VERSION 5.8 ;
BUSBITCHARS "[]" ;
DIVIDERCHAR "/" ;
UNITS
    DATABASE MICRONS 1000 ;
END UNITS

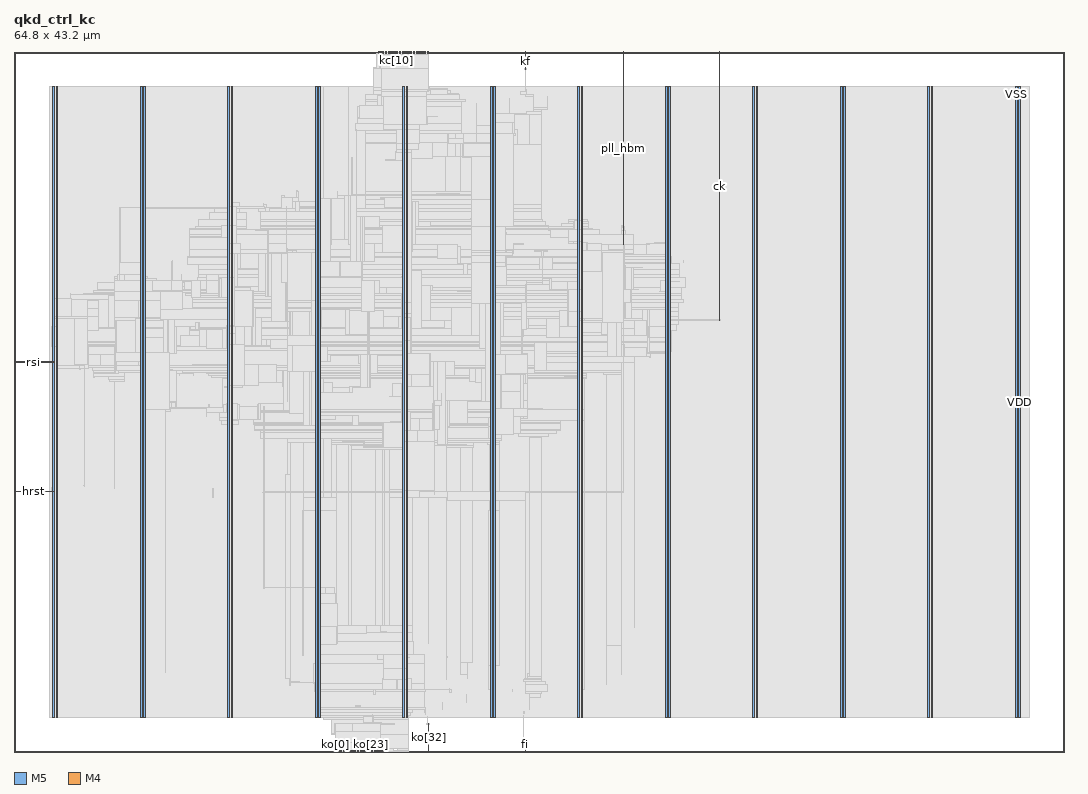
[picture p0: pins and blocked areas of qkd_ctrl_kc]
MACRO qkd_ctrl_kc
  FOREIGN qkd_ctrl_kc 0 0 ;
  CLASS BLOCK ;
  SIZE 64.8 BY 43.2 ;
  PIN ck
    DIRECTION INPUT ;
    USE SIGNAL ;
    PORT
      LAYER M5 ;
        RECT  43.536 43.116 43.56 43.2 ;
    END
    PORT
      LAYER M5 ;
        RECT  43.536 26.629 43.56 43.152 ;
    END
  END ck
  PIN fi
    DIRECTION INPUT ;
    USE SIGNAL ;
    PORT
      LAYER M5 ;
        RECT  31.536 0 31.56 0.084 ;
    END
    PORT
      LAYER M5 ;
        RECT  31.536 0.016 31.56 0.611 ;
    END
  END fi
  PIN hrst
    DIRECTION INPUT ;
    USE SIGNAL ;
    PORT
      LAYER M4 ;
        RECT  0 16.08 0.084 16.104 ;
    END
    PORT
      LAYER M4 ;
        RECT  0.06 16.08 2.408 16.104 ;
    END
  END hrst
  PIN kc[0]
    DIRECTION INPUT ;
    USE SIGNAL ;
    PORT
      LAYER M5 ;
        RECT  22.608 43.116 22.632 43.2 ;
    END
  END kc[0]
  PIN kc[10]
    DIRECTION INPUT ;
    USE SIGNAL ;
    PORT
      LAYER M5 ;
        RECT  23.568 43.116 23.592 43.2 ;
    END
  END kc[10]
  PIN kc[11]
    DIRECTION INPUT ;
    USE SIGNAL ;
    PORT
      LAYER M5 ;
        RECT  23.664 43.116 23.688 43.2 ;
    END
  END kc[11]
  PIN kc[12]
    DIRECTION INPUT ;
    USE SIGNAL ;
    PORT
      LAYER M5 ;
        RECT  23.76 43.116 23.784 43.2 ;
    END
  END kc[12]
  PIN kc[13]
    DIRECTION INPUT ;
    USE SIGNAL ;
    PORT
      LAYER M5 ;
        RECT  23.856 43.116 23.88 43.2 ;
    END
  END kc[13]
  PIN kc[14]
    DIRECTION INPUT ;
    USE SIGNAL ;
    PORT
      LAYER M5 ;
        RECT  23.952 43.116 23.976 43.2 ;
    END
  END kc[14]
  PIN kc[15]
    DIRECTION INPUT ;
    USE SIGNAL ;
    PORT
      LAYER M5 ;
        RECT  24.048 43.116 24.072 43.2 ;
    END
  END kc[15]
  PIN kc[16]
    DIRECTION INPUT ;
    USE SIGNAL ;
    PORT
      LAYER M5 ;
        RECT  24.144 43.116 24.168 43.2 ;
    END
  END kc[16]
  PIN kc[17]
    DIRECTION INPUT ;
    USE SIGNAL ;
    PORT
      LAYER M5 ;
        RECT  24.24 43.116 24.264 43.2 ;
    END
  END kc[17]
  PIN kc[18]
    DIRECTION INPUT ;
    USE SIGNAL ;
    PORT
      LAYER M5 ;
        RECT  24.336 43.116 24.36 43.2 ;
    END
  END kc[18]
  PIN kc[19]
    DIRECTION INPUT ;
    USE SIGNAL ;
    PORT
      LAYER M5 ;
        RECT  24.432 43.116 24.456 43.2 ;
    END
  END kc[19]
  PIN kc[1]
    DIRECTION INPUT ;
    USE SIGNAL ;
    PORT
      LAYER M5 ;
        RECT  22.704 43.116 22.728 43.2 ;
    END
  END kc[1]
  PIN kc[20]
    DIRECTION INPUT ;
    USE SIGNAL ;
    PORT
      LAYER M5 ;
        RECT  24.528 43.116 24.552 43.2 ;
    END
  END kc[20]
  PIN kc[21]
    DIRECTION INPUT ;
    USE SIGNAL ;
    PORT
      LAYER M5 ;
        RECT  24.624 43.116 24.648 43.2 ;
    END
  END kc[21]
  PIN kc[22]
    DIRECTION INPUT ;
    USE SIGNAL ;
    PORT
      LAYER M5 ;
        RECT  24.72 43.116 24.744 43.2 ;
    END
  END kc[22]
  PIN kc[23]
    DIRECTION INPUT ;
    USE SIGNAL ;
    PORT
      LAYER M5 ;
        RECT  24.816 43.116 24.84 43.2 ;
    END
  END kc[23]
  PIN kc[24]
    DIRECTION INPUT ;
    USE SIGNAL ;
    PORT
      LAYER M5 ;
        RECT  24.912 43.116 24.936 43.2 ;
    END
  END kc[24]
  PIN kc[25]
    DIRECTION INPUT ;
    USE SIGNAL ;
    PORT
      LAYER M5 ;
        RECT  25.008 43.116 25.032 43.2 ;
    END
  END kc[25]
  PIN kc[26]
    DIRECTION INPUT ;
    USE SIGNAL ;
    PORT
      LAYER M5 ;
        RECT  25.104 43.116 25.128 43.2 ;
    END
  END kc[26]
  PIN kc[27]
    DIRECTION INPUT ;
    USE SIGNAL ;
    PORT
      LAYER M5 ;
        RECT  25.2 43.116 25.224 43.2 ;
    END
  END kc[27]
  PIN kc[28]
    DIRECTION INPUT ;
    USE SIGNAL ;
    PORT
      LAYER M5 ;
        RECT  25.296 43.116 25.32 43.2 ;
    END
  END kc[28]
  PIN kc[29]
    DIRECTION INPUT ;
    USE SIGNAL ;
    PORT
      LAYER M5 ;
        RECT  25.392 43.116 25.416 43.2 ;
    END
  END kc[29]
  PIN kc[2]
    DIRECTION INPUT ;
    USE SIGNAL ;
    PORT
      LAYER M5 ;
        RECT  22.8 43.116 22.824 43.2 ;
    END
  END kc[2]
  PIN kc[30]
    DIRECTION INPUT ;
    USE SIGNAL ;
    PORT
      LAYER M5 ;
        RECT  25.488 43.116 25.512 43.2 ;
    END
  END kc[30]
  PIN kc[31]
    DIRECTION INPUT ;
    USE SIGNAL ;
    PORT
      LAYER M5 ;
        RECT  25.584 43.116 25.608 43.2 ;
    END
  END kc[31]
  PIN kc[32]
    DIRECTION INPUT ;
    USE SIGNAL ;
    PORT
      LAYER M5 ;
        RECT  22.512 43.116 22.536 43.2 ;
    END
  END kc[32]
  PIN kc[3]
    DIRECTION INPUT ;
    USE SIGNAL ;
    PORT
      LAYER M5 ;
        RECT  22.896 43.116 22.92 43.2 ;
    END
  END kc[3]
  PIN kc[4]
    DIRECTION INPUT ;
    USE SIGNAL ;
    PORT
      LAYER M5 ;
        RECT  22.992 43.116 23.016 43.2 ;
    END
  END kc[4]
  PIN kc[5]
    DIRECTION INPUT ;
    USE SIGNAL ;
    PORT
      LAYER M5 ;
        RECT  23.088 43.116 23.112 43.2 ;
    END
  END kc[5]
  PIN kc[6]
    DIRECTION INPUT ;
    USE SIGNAL ;
    PORT
      LAYER M5 ;
        RECT  23.184 43.116 23.208 43.2 ;
    END
  END kc[6]
  PIN kc[7]
    DIRECTION INPUT ;
    USE SIGNAL ;
    PORT
      LAYER M5 ;
        RECT  23.28 43.116 23.304 43.2 ;
    END
  END kc[7]
  PIN kc[8]
    DIRECTION INPUT ;
    USE SIGNAL ;
    PORT
      LAYER M5 ;
        RECT  23.376 43.116 23.4 43.2 ;
    END
  END kc[8]
  PIN kc[9]
    DIRECTION INPUT ;
    USE SIGNAL ;
    PORT
      LAYER M5 ;
        RECT  23.472 43.116 23.496 43.2 ;
    END
  END kc[9]
  PIN kf
    DIRECTION OUTPUT ;
    USE SIGNAL ;
    PORT
      LAYER M5 ;
        RECT  31.536 43.116 31.56 43.2 ;
    END
    PORT
      LAYER M5 ;
        RECT  31.536 42.133 31.56 43.152 ;
    END
  END kf
  PIN ko[0]
    DIRECTION OUTPUT ;
    USE SIGNAL ;
    PORT
      LAYER M5 ;
        RECT  19.824 0 19.848 0.084 ;
    END
  END ko[0]
  PIN ko[10]
    DIRECTION OUTPUT ;
    USE SIGNAL ;
    PORT
      LAYER M5 ;
        RECT  20.784 0 20.808 0.084 ;
    END
  END ko[10]
  PIN ko[11]
    DIRECTION OUTPUT ;
    USE SIGNAL ;
    PORT
      LAYER M5 ;
        RECT  20.88 0 20.904 0.084 ;
    END
  END ko[11]
  PIN ko[12]
    DIRECTION OUTPUT ;
    USE SIGNAL ;
    PORT
      LAYER M5 ;
        RECT  20.976 0 21 0.084 ;
    END
  END ko[12]
  PIN ko[13]
    DIRECTION OUTPUT ;
    USE SIGNAL ;
    PORT
      LAYER M5 ;
        RECT  21.072 0 21.096 0.084 ;
    END
  END ko[13]
  PIN ko[14]
    DIRECTION OUTPUT ;
    USE SIGNAL ;
    PORT
      LAYER M5 ;
        RECT  21.168 0 21.192 0.084 ;
    END
  END ko[14]
  PIN ko[15]
    DIRECTION OUTPUT ;
    USE SIGNAL ;
    PORT
      LAYER M5 ;
        RECT  21.264 0 21.288 0.084 ;
    END
  END ko[15]
  PIN ko[16]
    DIRECTION OUTPUT ;
    USE SIGNAL ;
    PORT
      LAYER M5 ;
        RECT  21.36 0 21.384 0.084 ;
    END
  END ko[16]
  PIN ko[17]
    DIRECTION OUTPUT ;
    USE SIGNAL ;
    PORT
      LAYER M5 ;
        RECT  21.456 0 21.48 0.084 ;
    END
  END ko[17]
  PIN ko[18]
    DIRECTION OUTPUT ;
    USE SIGNAL ;
    PORT
      LAYER M5 ;
        RECT  21.552 0 21.576 0.084 ;
    END
  END ko[18]
  PIN ko[19]
    DIRECTION OUTPUT ;
    USE SIGNAL ;
    PORT
      LAYER M5 ;
        RECT  21.648 0 21.672 0.084 ;
    END
  END ko[19]
  PIN ko[1]
    DIRECTION OUTPUT ;
    USE SIGNAL ;
    PORT
      LAYER M5 ;
        RECT  19.92 0 19.944 0.084 ;
    END
  END ko[1]
  PIN ko[20]
    DIRECTION OUTPUT ;
    USE SIGNAL ;
    PORT
      LAYER M5 ;
        RECT  21.744 0 21.768 0.084 ;
    END
  END ko[20]
  PIN ko[21]
    DIRECTION OUTPUT ;
    USE SIGNAL ;
    PORT
      LAYER M5 ;
        RECT  21.84 0 21.864 0.084 ;
    END
  END ko[21]
  PIN ko[22]
    DIRECTION OUTPUT ;
    USE SIGNAL ;
    PORT
      LAYER M5 ;
        RECT  21.936 0 21.96 0.084 ;
    END
  END ko[22]
  PIN ko[23]
    DIRECTION OUTPUT ;
    USE SIGNAL ;
    PORT
      LAYER M5 ;
        RECT  22.032 0 22.056 0.084 ;
    END
  END ko[23]
  PIN ko[24]
    DIRECTION OUTPUT ;
    USE SIGNAL ;
    PORT
      LAYER M5 ;
        RECT  22.128 0 22.152 0.084 ;
    END
  END ko[24]
  PIN ko[25]
    DIRECTION OUTPUT ;
    USE SIGNAL ;
    PORT
      LAYER M5 ;
        RECT  22.224 0 22.248 0.084 ;
    END
  END ko[25]
  PIN ko[26]
    DIRECTION OUTPUT ;
    USE SIGNAL ;
    PORT
      LAYER M5 ;
        RECT  22.32 0 22.344 0.084 ;
    END
  END ko[26]
  PIN ko[27]
    DIRECTION OUTPUT ;
    USE SIGNAL ;
    PORT
      LAYER M5 ;
        RECT  22.416 0 22.44 0.084 ;
    END
  END ko[27]
  PIN ko[28]
    DIRECTION OUTPUT ;
    USE SIGNAL ;
    PORT
      LAYER M5 ;
        RECT  22.512 0 22.536 0.084 ;
    END
  END ko[28]
  PIN ko[29]
    DIRECTION OUTPUT ;
    USE SIGNAL ;
    PORT
      LAYER M5 ;
        RECT  22.608 0 22.632 0.084 ;
    END
  END ko[29]
  PIN ko[2]
    DIRECTION OUTPUT ;
    USE SIGNAL ;
    PORT
      LAYER M5 ;
        RECT  20.016 0 20.04 0.084 ;
    END
  END ko[2]
  PIN ko[30]
    DIRECTION OUTPUT ;
    USE SIGNAL ;
    PORT
      LAYER M5 ;
        RECT  22.704 0 22.728 0.084 ;
    END
  END ko[30]
  PIN ko[31]
    DIRECTION OUTPUT ;
    USE SIGNAL ;
    PORT
      LAYER M5 ;
        RECT  22.8 0 22.824 0.084 ;
    END
  END ko[31]
  PIN ko[32]
    DIRECTION OUTPUT ;
    USE SIGNAL ;
    PORT
      LAYER M5 ;
        RECT  25.584 0 25.608 0.084 ;
    END
    PORT
      LAYER M5 ;
        RECT  25.584 0.016 25.608 1.763 ;
    END
  END ko[32]
  PIN ko[3]
    DIRECTION OUTPUT ;
    USE SIGNAL ;
    PORT
      LAYER M5 ;
        RECT  20.112 0 20.136 0.084 ;
    END
  END ko[3]
  PIN ko[4]
    DIRECTION OUTPUT ;
    USE SIGNAL ;
    PORT
      LAYER M5 ;
        RECT  20.208 0 20.232 0.084 ;
    END
  END ko[4]
  PIN ko[5]
    DIRECTION OUTPUT ;
    USE SIGNAL ;
    PORT
      LAYER M5 ;
        RECT  20.304 0 20.328 0.084 ;
    END
  END ko[5]
  PIN ko[6]
    DIRECTION OUTPUT ;
    USE SIGNAL ;
    PORT
      LAYER M5 ;
        RECT  20.4 0 20.424 0.084 ;
    END
  END ko[6]
  PIN ko[7]
    DIRECTION OUTPUT ;
    USE SIGNAL ;
    PORT
      LAYER M5 ;
        RECT  20.496 0 20.52 0.084 ;
    END
  END ko[7]
  PIN ko[8]
    DIRECTION OUTPUT ;
    USE SIGNAL ;
    PORT
      LAYER M5 ;
        RECT  20.592 0 20.616 0.084 ;
    END
  END ko[8]
  PIN ko[9]
    DIRECTION OUTPUT ;
    USE SIGNAL ;
    PORT
      LAYER M5 ;
        RECT  20.688 0 20.712 0.084 ;
    END
  END ko[9]
  PIN pll_hbm
    DIRECTION INPUT ;
    USE SIGNAL ;
    PORT
      LAYER M5 ;
        RECT  37.584 43.116 37.608 43.2 ;
    END
    PORT
      LAYER M5 ;
        RECT  37.584 31.331 37.608 43.152 ;
    END
  END pll_hbm
  PIN rsi
    DIRECTION INPUT ;
    USE SIGNAL ;
    PORT
      LAYER M4 ;
        RECT  0 24.048 0.084 24.072 ;
    END
    PORT
      LAYER M4 ;
        RECT  0.06 24.048 2.408 24.072 ;
    END
  END rsi
  PIN VDD
    DIRECTION INOUT ;
    USE POWER ;
    PORT
      LAYER M5 ;
        RECT  61.992 2.151 62.112 41.049 ;
        RECT  56.592 2.151 56.712 41.049 ;
        RECT  51.192 2.151 51.312 41.049 ;
        RECT  45.792 2.151 45.912 41.049 ;
        RECT  40.392 2.151 40.512 41.049 ;
        RECT  34.992 2.151 35.112 41.049 ;
        RECT  29.592 2.151 29.712 41.049 ;
        RECT  24.192 2.151 24.312 41.049 ;
        RECT  18.792 2.151 18.912 41.049 ;
        RECT  13.392 2.151 13.512 41.049 ;
        RECT  7.992 2.151 8.112 41.049 ;
        RECT  2.592 2.151 2.712 41.049 ;
    END
  END VDD
  PIN VSS
    DIRECTION INOUT ;
    USE GROUND ;
    PORT
      LAYER M5 ;
        RECT  61.8 2.137 61.92 41.063 ;
        RECT  56.4 2.137 56.52 41.063 ;
        RECT  51 2.137 51.12 41.063 ;
        RECT  45.6 2.137 45.72 41.063 ;
        RECT  40.2 2.137 40.32 41.063 ;
        RECT  34.8 2.137 34.92 41.063 ;
        RECT  29.4 2.137 29.52 41.063 ;
        RECT  24 2.137 24.12 41.063 ;
        RECT  18.6 2.137 18.72 41.063 ;
        RECT  13.2 2.137 13.32 41.063 ;
        RECT  7.8 2.137 7.92 41.063 ;
        RECT  2.4 2.137 2.52 41.063 ;
    END
  END VSS
  # OT_OBS_CLOSED layer=M5 d_um=1.536 added=60
  OBS
    LAYER RVTN ;
     RECT  2.16 2.16 62.64 2.295 ;
     RECT  2.16 2.565 62.64 2.835 ;
     RECT  2.16 3.105 62.64 3.375 ;
     RECT  2.16 3.645 62.64 3.915 ;
     RECT  2.16 4.185 62.64 4.455 ;
     RECT  2.16 4.725 62.64 4.995 ;
     RECT  2.16 5.265 62.64 5.535 ;
     RECT  2.16 5.805 62.64 6.075 ;
     RECT  2.16 6.345 62.64 6.615 ;
     RECT  2.16 6.885 62.64 7.155 ;
     RECT  2.16 7.425 62.64 7.695 ;
     RECT  2.16 7.965 62.64 8.235 ;
     RECT  2.16 8.505 62.64 8.775 ;
     RECT  2.16 9.045 62.64 9.315 ;
     RECT  2.16 9.585 62.64 9.855 ;
     RECT  2.16 10.125 62.64 10.395 ;
     RECT  2.16 10.665 62.64 10.935 ;
     RECT  2.16 11.205 62.64 11.475 ;
     RECT  2.16 11.745 62.64 12.015 ;
     RECT  2.16 12.285 62.64 12.555 ;
     RECT  2.16 12.825 62.64 13.095 ;
     RECT  2.16 13.365 62.64 13.635 ;
     RECT  2.16 13.905 62.64 14.175 ;
     RECT  2.16 14.445 62.64 14.715 ;
     RECT  2.16 14.985 62.64 15.255 ;
     RECT  2.16 15.525 62.64 15.795 ;
     RECT  2.16 16.065 62.64 16.335 ;
     RECT  2.16 16.605 62.64 16.875 ;
     RECT  2.16 17.145 62.64 17.415 ;
     RECT  2.16 17.685 62.64 17.955 ;
     RECT  2.16 18.225 62.64 18.495 ;
     RECT  2.16 18.765 62.64 19.035 ;
     RECT  2.16 19.305 62.64 19.575 ;
     RECT  2.16 19.845 62.64 20.115 ;
     RECT  2.16 20.385 62.64 20.655 ;
     RECT  2.16 20.925 62.64 21.195 ;
     RECT  2.16 21.465 62.64 21.735 ;
     RECT  2.16 22.005 62.64 22.275 ;
     RECT  2.16 22.545 62.64 22.815 ;
     RECT  2.16 23.085 62.64 23.355 ;
     RECT  2.16 23.625 62.64 23.895 ;
     RECT  2.16 24.165 62.64 24.435 ;
     RECT  2.16 24.705 62.64 24.975 ;
     RECT  2.16 25.245 62.64 25.515 ;
     RECT  2.16 25.785 62.64 26.055 ;
     RECT  2.16 26.325 62.64 26.595 ;
     RECT  2.16 26.865 62.64 27.135 ;
     RECT  2.16 27.405 62.64 27.675 ;
     RECT  2.16 27.945 62.64 28.215 ;
     RECT  2.16 28.485 62.64 28.755 ;
     RECT  2.16 29.025 62.64 29.295 ;
     RECT  2.16 29.565 62.64 29.835 ;
     RECT  2.16 30.105 62.64 30.375 ;
     RECT  2.16 30.645 62.64 30.915 ;
     RECT  2.16 31.185 62.64 31.455 ;
     RECT  2.16 31.725 62.64 31.995 ;
     RECT  2.16 32.265 62.64 32.535 ;
     RECT  2.16 32.805 62.64 33.075 ;
     RECT  2.16 33.345 62.64 33.615 ;
     RECT  2.16 33.885 62.64 34.155 ;
     RECT  2.16 34.425 62.64 34.695 ;
     RECT  2.16 34.965 62.64 35.235 ;
     RECT  2.16 35.505 62.64 35.775 ;
     RECT  2.16 36.045 62.64 36.315 ;
     RECT  2.16 36.585 62.64 36.855 ;
     RECT  2.16 37.125 62.64 37.395 ;
     RECT  2.16 37.665 62.64 37.935 ;
     RECT  2.16 38.205 62.64 38.475 ;
     RECT  2.16 38.745 62.64 39.015 ;
     RECT  2.16 39.285 62.64 39.555 ;
     RECT  2.16 39.825 62.64 40.095 ;
     RECT  2.16 40.365 62.64 40.635 ;
     RECT  2.16 40.905 62.64 41.04 ;
    LAYER RVTP ;
     RECT  2.16 2.295 62.64 2.565 ;
     RECT  2.16 2.835 62.64 3.105 ;
     RECT  2.16 3.375 62.64 3.645 ;
     RECT  2.16 3.915 62.64 4.185 ;
     RECT  2.16 4.455 62.64 4.725 ;
     RECT  2.16 4.995 62.64 5.265 ;
     RECT  2.16 5.535 62.64 5.805 ;
     RECT  2.16 6.075 62.64 6.345 ;
     RECT  2.16 6.615 62.64 6.885 ;
     RECT  2.16 7.155 62.64 7.425 ;
     RECT  2.16 7.695 62.64 7.965 ;
     RECT  2.16 8.235 62.64 8.505 ;
     RECT  2.16 8.775 62.64 9.045 ;
     RECT  2.16 9.315 62.64 9.585 ;
     RECT  2.16 9.855 62.64 10.125 ;
     RECT  2.16 10.395 62.64 10.665 ;
     RECT  2.16 10.935 62.64 11.205 ;
     RECT  2.16 11.475 62.64 11.745 ;
     RECT  2.16 12.015 62.64 12.285 ;
     RECT  2.16 12.555 62.64 12.825 ;
     RECT  2.16 13.095 62.64 13.365 ;
     RECT  2.16 13.635 62.64 13.905 ;
     RECT  2.16 14.175 62.64 14.445 ;
     RECT  2.16 14.715 62.64 14.985 ;
     RECT  2.16 15.255 62.64 15.525 ;
     RECT  2.16 15.795 62.64 16.065 ;
     RECT  2.16 16.335 62.64 16.605 ;
     RECT  2.16 16.875 62.64 17.145 ;
     RECT  2.16 17.415 62.64 17.685 ;
     RECT  2.16 17.955 62.64 18.225 ;
     RECT  2.16 18.495 62.64 18.765 ;
     RECT  2.16 19.035 62.64 19.305 ;
     RECT  2.16 19.575 62.64 19.845 ;
     RECT  2.16 20.115 62.64 20.385 ;
     RECT  2.16 20.655 62.64 20.925 ;
     RECT  2.16 21.195 62.64 21.465 ;
     RECT  2.16 21.735 62.64 22.005 ;
     RECT  2.16 22.275 62.64 22.545 ;
     RECT  2.16 22.815 62.64 23.085 ;
     RECT  2.16 23.355 62.64 23.625 ;
     RECT  2.16 23.895 62.64 24.165 ;
     RECT  2.16 24.435 62.64 24.705 ;
     RECT  2.16 24.975 62.64 25.245 ;
     RECT  2.16 25.515 62.64 25.785 ;
     RECT  2.16 26.055 62.64 26.325 ;
     RECT  2.16 26.595 62.64 26.865 ;
     RECT  2.16 27.135 62.64 27.405 ;
     RECT  2.16 27.675 62.64 27.945 ;
     RECT  2.16 28.215 62.64 28.485 ;
     RECT  2.16 28.755 62.64 29.025 ;
     RECT  2.16 29.295 62.64 29.565 ;
     RECT  2.16 29.835 62.64 30.105 ;
     RECT  2.16 30.375 62.64 30.645 ;
     RECT  2.16 30.915 62.64 31.185 ;
     RECT  2.16 31.455 62.64 31.725 ;
     RECT  2.16 31.995 62.64 32.265 ;
     RECT  2.16 32.535 62.64 32.805 ;
     RECT  2.16 33.075 62.64 33.345 ;
     RECT  2.16 33.615 62.64 33.885 ;
     RECT  2.16 34.155 62.64 34.425 ;
     RECT  2.16 34.695 62.64 34.965 ;
     RECT  2.16 35.235 62.64 35.505 ;
     RECT  2.16 35.775 62.64 36.045 ;
     RECT  2.16 36.315 62.64 36.585 ;
     RECT  2.16 36.855 62.64 37.125 ;
     RECT  2.16 37.395 62.64 37.665 ;
     RECT  2.16 37.935 62.64 38.205 ;
     RECT  2.16 38.475 62.64 38.745 ;
     RECT  2.16 39.015 62.64 39.285 ;
     RECT  2.16 39.555 62.64 39.825 ;
     RECT  2.16 40.095 62.64 40.365 ;
     RECT  2.16 40.635 62.64 40.905 ;
    LAYER M1 ;
     RECT  2.16 2.151 62.64 41.049 ;
    LAYER M2 ;
     RECT  2.16 2.151 19.111 41.049 ;
     RECT  19.111 2.034 20.651 41.049 ;
     RECT  20.651 2.151 22.747 41.049 ;
     RECT  22.747 2.106 22.847 41.049 ;
     RECT  22.847 2.151 62.64 41.049 ;
    LAYER M3 ;
     RECT  22.536 0.043 22.554 0.091 ;
     RECT  24.336 0.043 24.354 0.091 ;
     RECT  19.944 0.091 20.754 0.139 ;
     RECT  21.888 0.091 22.554 0.139 ;
     RECT  19.836 0.139 22.698 0.187 ;
     RECT  23.688 0.091 24.354 0.187 ;
     RECT  19.836 0.187 24.354 1.099 ;
     RECT  19.62 1.099 24.354 2.029 ;
     RECT  19.116 2.029 24.354 2.143 ;
     RECT  25.488 1.723 25.506 2.219 ;
     RECT  31.428 0.571 31.446 2.255 ;
     RECT  18.615 2.143 24.354 2.263 ;
     RECT  2.415 2.143 2.505 2.413 ;
     RECT  7.815 2.143 7.905 2.413 ;
     RECT  13.215 2.143 13.305 2.413 ;
     RECT  29.415 2.143 29.505 2.413 ;
     RECT  34.815 2.143 34.905 2.413 ;
     RECT  40.215 2.143 40.305 2.413 ;
     RECT  45.615 2.143 45.705 2.413 ;
     RECT  51.015 2.143 51.105 2.413 ;
     RECT  56.415 2.143 56.505 2.413 ;
     RECT  61.815 2.143 61.905 2.413 ;
     RECT  18.615 2.263 24.498 2.461 ;
     RECT  25.38 2.335 25.398 2.461 ;
     RECT  31.464 2.371 31.482 2.489 ;
     RECT  18.615 2.461 24.57 2.641 ;
     RECT  25.344 2.461 25.398 2.641 ;
     RECT  18.615 2.641 25.398 2.759 ;
     RECT  26.424 2.641 26.442 3.029 ;
     RECT  31.788 2.641 31.806 3.379 ;
     RECT  27.936 3.073 27.954 3.569 ;
     RECT  31.788 3.379 32.49 3.604 ;
     RECT  31.788 3.604 32.526 3.613 ;
     RECT  18.615 2.759 25.362 3.721 ;
     RECT  31.536 3.613 32.526 3.721 ;
     RECT  18.54 3.721 25.398 3.839 ;
     RECT  30.744 3.721 30.762 3.839 ;
     RECT  29.415 2.413 29.697 3.847 ;
     RECT  26.856 3.685 26.982 3.869 ;
     RECT  34.815 2.413 35.097 3.883 ;
     RECT  26.856 3.869 26.874 3.911 ;
     RECT  31.536 3.721 32.922 4.181 ;
     RECT  18.54 3.839 25.362 4.225 ;
     RECT  17.028 4.081 17.046 4.267 ;
     RECT  31.536 4.181 32.814 4.351 ;
     RECT  17.028 4.267 17.622 4.379 ;
     RECT  31.464 4.351 32.814 4.379 ;
     RECT  31.464 4.379 32.562 4.487 ;
     RECT  17.028 4.379 17.046 4.531 ;
     RECT  31.536 4.487 32.562 4.559 ;
     RECT  31.68 4.559 32.562 4.649 ;
     RECT  31.68 4.649 31.806 4.685 ;
     RECT  27.972 4.531 27.99 4.801 ;
     RECT  31.716 4.685 31.806 4.829 ;
     RECT  29.268 3.847 29.697 5.341 ;
     RECT  18.504 4.225 25.362 5.459 ;
     RECT  27.54 4.801 27.99 5.503 ;
     RECT  26.676 4.459 26.694 5.809 ;
     RECT  26.676 5.809 26.766 5.909 ;
     RECT  18.615 5.459 25.362 5.999 ;
     RECT  36.54 4.189 36.558 6.547 ;
     RECT  37.476 4.765 37.494 6.547 ;
     RECT  18.615 5.999 24.642 6.809 ;
     RECT  18.615 6.809 24.57 7.385 ;
     RECT  20.664 7.385 24.57 7.805 ;
     RECT  18.615 7.385 19.89 9.115 ;
     RECT  17.82 5.971 17.838 14.881 ;
     RECT  18.615 9.115 19.926 14.881 ;
     RECT  17.82 14.881 19.926 14.909 ;
     RECT  29.268 5.341 29.97 14.909 ;
     RECT  26.676 5.909 26.694 15.547 ;
     RECT  23.148 7.805 24.57 15.691 ;
     RECT  25.56 6.691 25.578 15.691 ;
     RECT  17.892 14.909 19.926 15.719 ;
     RECT  26.676 15.547 26.802 15.725 ;
     RECT  15.408 15.961 15.426 16.013 ;
     RECT  15.516 16.024 15.534 16.061 ;
     RECT  2.415 2.413 2.697 16.075 ;
     RECT  23.148 15.691 25.578 16.205 ;
     RECT  12.276 15.691 12.294 16.259 ;
     RECT  2.304 16.075 2.697 16.295 ;
     RECT  4.32 16.405 4.338 16.445 ;
     RECT  16.776 4.531 17.046 17.141 ;
     RECT  20.808 7.805 22.302 18.697 ;
     RECT  23.148 16.205 24.57 18.697 ;
     RECT  26.676 15.725 26.694 18.805 ;
     RECT  27.54 5.503 28.314 18.805 ;
     RECT  20.808 18.697 24.57 18.931 ;
     RECT  25.56 16.205 25.578 18.931 ;
     RECT  26.676 18.805 28.386 18.931 ;
     RECT  29.34 14.909 29.97 18.967 ;
     RECT  19.62 15.719 19.926 19.003 ;
     RECT  20.772 18.931 24.57 19.003 ;
     RECT  19.62 19.003 24.57 19.075 ;
     RECT  25.56 18.931 28.386 19.075 ;
     RECT  16.848 17.141 17.046 19.111 ;
     RECT  17.892 15.719 18.897 19.111 ;
     RECT  19.62 19.075 28.386 19.111 ;
     RECT  29.196 18.967 29.97 19.111 ;
     RECT  19.62 19.111 29.97 19.201 ;
     RECT  15.228 19.339 15.822 19.345 ;
     RECT  16.848 19.111 18.897 19.345 ;
     RECT  19.62 19.201 30.078 19.345 ;
     RECT  15.228 19.345 30.078 19.373 ;
     RECT  31.788 4.829 31.806 19.381 ;
     RECT  32.544 4.649 32.562 19.381 ;
     RECT  31.788 19.381 32.562 19.471 ;
     RECT  31.104 19.471 32.958 19.651 ;
     RECT  15.228 19.373 24.678 19.741 ;
     RECT  15.192 19.741 24.678 19.849 ;
     RECT  31.104 19.651 33.462 19.849 ;
     RECT  31.104 19.849 33.75 19.885 ;
     RECT  14.868 19.849 24.678 19.921 ;
     RECT  25.524 19.373 30.078 20.011 ;
     RECT  14.832 19.921 24.678 20.155 ;
     RECT  25.524 20.011 30.15 20.155 ;
     RECT  13.215 2.413 13.497 20.191 ;
     RECT  14.832 20.155 30.15 20.191 ;
     RECT  14.76 20.191 30.15 20.281 ;
     RECT  31.068 19.885 33.75 20.281 ;
     RECT  14.76 20.281 33.75 20.345 ;
     RECT  12.78 20.191 13.842 20.461 ;
     RECT  30.78 20.345 33.75 20.461 ;
     RECT  34.815 3.883 35.19 20.461 ;
     RECT  12.708 20.461 13.842 20.659 ;
     RECT  11.88 20.731 11.898 20.923 ;
     RECT  12.708 20.659 13.878 20.923 ;
     RECT  11.88 20.923 13.878 20.929 ;
     RECT  14.76 20.345 30.006 20.929 ;
     RECT  11.88 20.929 30.006 20.957 ;
     RECT  9.36 4.891 9.378 21.001 ;
     RECT  12.024 20.957 30.006 21.029 ;
     RECT  12.852 21.029 30.006 21.127 ;
     RECT  30.78 20.461 35.19 21.127 ;
     RECT  9.36 21.001 9.63 21.211 ;
     RECT  12.024 21.029 12.042 21.425 ;
     RECT  9.36 21.211 9.702 21.541 ;
     RECT  9.36 21.541 9.99 21.677 ;
     RECT  6.192 16.267 6.21 22.891 ;
     RECT  5.904 22.891 6.822 23.017 ;
     RECT  12.852 21.127 35.19 23.053 ;
     RECT  12.852 23.053 35.334 23.125 ;
     RECT  4.932 23.089 4.95 23.161 ;
     RECT  5.832 23.017 6.822 23.161 ;
     RECT  12.168 23.125 35.334 23.251 ;
     RECT  36.54 6.547 37.494 23.287 ;
     RECT  9.36 21.677 9.378 23.359 ;
     RECT  10.224 23.251 10.242 23.359 ;
     RECT  11.988 23.251 35.334 23.359 ;
     RECT  9.36 23.359 10.242 23.371 ;
     RECT  11.088 23.251 11.106 23.371 ;
     RECT  9.36 23.371 11.106 23.395 ;
     RECT  11.88 23.359 35.334 23.395 ;
     RECT  4.932 23.161 6.822 23.431 ;
     RECT  7.815 2.413 8.097 23.431 ;
     RECT  8.892 23.395 35.442 23.431 ;
     RECT  36.36 23.287 37.494 23.431 ;
     RECT  8.892 23.431 37.494 23.549 ;
     RECT  4.932 23.431 8.097 23.557 ;
     RECT  8.892 23.549 32.094 23.557 ;
     RECT  4.068 23.629 4.086 23.701 ;
     RECT  4.824 23.557 32.094 23.701 ;
     RECT  4.068 23.701 32.094 23.851 ;
     RECT  3.744 23.851 32.094 23.855 ;
     RECT  2.415 16.295 2.697 23.899 ;
     RECT  3.744 23.855 4.554 23.935 ;
     RECT  2.415 23.899 2.79 23.971 ;
     RECT  3.636 23.935 4.554 23.971 ;
     RECT  2.415 23.971 4.554 24.043 ;
     RECT  32.868 23.549 37.494 24.061 ;
     RECT  38.304 7.663 38.322 24.061 ;
     RECT  2.304 24.043 4.554 24.125 ;
     RECT  32.868 24.061 38.322 24.379 ;
     RECT  39.24 24.331 39.258 24.379 ;
     RECT  32.868 24.379 39.258 24.601 ;
     RECT  40.215 2.413 40.497 24.601 ;
     RECT  32.868 24.601 40.497 24.709 ;
     RECT  2.415 24.125 4.554 24.781 ;
     RECT  5.364 23.855 32.094 24.781 ;
     RECT  2.415 24.781 32.094 25.015 ;
     RECT  2.34 25.015 32.094 25.085 ;
     RECT  2.415 25.085 32.094 25.169 ;
     RECT  3.492 25.169 32.094 25.285 ;
     RECT  32.868 24.709 40.59 25.285 ;
     RECT  3.492 25.285 40.59 25.313 ;
     RECT  15.084 25.313 40.59 25.709 ;
     RECT  39.06 25.709 40.59 25.987 ;
     RECT  15.084 25.709 38.322 26.123 ;
     RECT  2.415 25.169 2.697 26.131 ;
     RECT  3.492 25.313 14.346 26.131 ;
     RECT  15.084 26.123 26.586 26.131 ;
     RECT  2.415 26.131 26.586 26.203 ;
     RECT  39.06 25.987 40.878 26.401 ;
     RECT  27.36 26.123 38.322 26.635 ;
     RECT  39.06 26.401 40.986 26.635 ;
     RECT  2.376 26.203 26.586 26.699 ;
     RECT  27.36 26.635 40.986 26.905 ;
     RECT  27.324 26.905 40.986 27.211 ;
     RECT  2.415 26.699 26.586 27.341 ;
     RECT  10.836 27.341 26.586 27.401 ;
     RECT  11.016 27.401 26.586 27.445 ;
     RECT  27.324 27.211 41.022 27.445 ;
     RECT  11.016 27.445 41.022 27.751 ;
     RECT  2.415 27.341 9.702 27.941 ;
     RECT  11.016 27.751 41.346 27.941 ;
     RECT  11.016 27.941 41.202 28.147 ;
     RECT  10.98 28.147 41.202 28.183 ;
     RECT  3.492 27.941 9.702 28.247 ;
     RECT  3.492 28.247 3.51 28.283 ;
     RECT  4.284 28.247 9.702 28.283 ;
     RECT  10.584 28.183 41.202 28.319 ;
     RECT  4.896 28.283 9.702 28.363 ;
     RECT  10.584 28.319 11.862 28.363 ;
     RECT  4.896 28.363 11.862 28.481 ;
     RECT  10.08 28.481 11.862 28.517 ;
     RECT  5.148 28.481 9.342 28.541 ;
     RECT  12.6 28.319 41.202 28.687 ;
     RECT  10.08 28.517 10.53 28.715 ;
     RECT  5.148 28.541 8.802 28.949 ;
     RECT  10.332 28.715 10.53 28.949 ;
     RECT  5.148 28.949 5.166 28.985 ;
     RECT  6.192 28.949 8.802 29.219 ;
     RECT  11.304 28.517 11.862 29.255 ;
     RECT  12.6 28.687 41.454 29.255 ;
     RECT  6.192 29.219 8.262 29.363 ;
     RECT  11.412 29.255 11.862 29.461 ;
     RECT  12.6 29.255 41.058 29.461 ;
     RECT  6.372 29.363 8.097 29.489 ;
     RECT  10.332 28.949 10.35 29.489 ;
     RECT  6.516 29.489 8.097 29.759 ;
     RECT  11.412 29.461 41.058 29.795 ;
     RECT  11.412 29.795 32.454 30.109 ;
     RECT  33.228 29.795 41.058 30.173 ;
     RECT  33.228 30.173 40.59 30.209 ;
     RECT  6.516 29.759 6.534 30.221 ;
     RECT  9.756 30.235 9.774 30.335 ;
     RECT  41.328 30.181 41.346 30.335 ;
     RECT  37.62 30.209 40.59 30.407 ;
     RECT  10.692 30.109 32.454 30.523 ;
     RECT  33.228 30.209 36.81 30.523 ;
     RECT  37.62 30.407 40.554 30.569 ;
     RECT  10.692 30.523 36.81 30.605 ;
     RECT  37.62 30.569 40.497 30.677 ;
     RECT  37.62 30.677 38.25 30.749 ;
     RECT  10.836 30.605 36.81 30.991 ;
     RECT  37.62 30.749 38.214 30.991 ;
     RECT  39.06 30.677 40.497 31.379 ;
     RECT  39.528 31.379 40.497 31.415 ;
     RECT  10.836 30.991 38.214 31.919 ;
     RECT  10.836 31.919 36.666 31.955 ;
     RECT  37.476 31.919 37.746 32.189 ;
     RECT  10.836 31.955 36.162 32.225 ;
     RECT  15.192 32.225 36.162 32.261 ;
     RECT  10.836 32.225 14.346 32.333 ;
     RECT  15.192 32.261 35.73 32.333 ;
     RECT  37.476 32.189 37.674 32.369 ;
     RECT  11.196 32.333 14.346 32.459 ;
     RECT  15.192 32.333 35.478 32.459 ;
     RECT  37.512 32.369 37.674 32.459 ;
     RECT  15.192 32.459 32.994 32.477 ;
     RECT  37.512 32.459 37.53 32.495 ;
     RECT  33.768 32.459 35.478 32.639 ;
     RECT  15.192 32.477 32.814 32.729 ;
     RECT  34.2 32.639 35.478 32.729 ;
     RECT  34.2 32.729 35.37 32.765 ;
     RECT  11.412 32.459 14.346 32.873 ;
     RECT  15.192 32.729 32.634 32.873 ;
     RECT  34.236 32.765 35.37 32.873 ;
     RECT  12.06 32.873 14.346 33.269 ;
     RECT  12.06 33.269 12.474 33.305 ;
     RECT  15.192 32.873 32.526 33.349 ;
     RECT  15.084 33.349 32.526 33.539 ;
     RECT  15.084 33.539 20.898 33.575 ;
     RECT  12.348 33.305 12.366 33.581 ;
     RECT  15.084 33.575 15.606 33.611 ;
     RECT  15.408 33.611 15.606 33.809 ;
     RECT  16.488 33.575 20.898 33.809 ;
     RECT  21.708 33.539 32.526 33.809 ;
     RECT  15.408 33.809 15.426 33.845 ;
     RECT  13.215 33.269 13.914 33.917 ;
     RECT  16.524 33.809 20.898 33.965 ;
     RECT  21.708 33.809 29.754 34.079 ;
     RECT  18.615 33.965 20.898 34.187 ;
     RECT  16.524 33.965 17.55 34.205 ;
     RECT  19.944 34.187 20.898 34.315 ;
     RECT  21.708 34.079 29.697 34.315 ;
     RECT  16.524 34.205 16.686 34.349 ;
     RECT  19.944 34.315 29.697 34.349 ;
     RECT  20.808 34.349 29.697 34.385 ;
     RECT  17.46 34.205 17.55 34.619 ;
     RECT  19.944 34.349 19.962 34.619 ;
     RECT  20.808 34.385 20.898 34.619 ;
     RECT  21.708 34.385 29.697 34.619 ;
     RECT  17.46 34.619 17.478 34.655 ;
     RECT  20.808 34.619 20.862 34.655 ;
     RECT  20.844 34.655 20.862 36.689 ;
     RECT  30.564 33.809 32.526 37.499 ;
     RECT  21.708 34.619 26.658 37.561 ;
     RECT  27.576 34.619 29.697 37.561 ;
     RECT  21.708 37.561 29.697 37.589 ;
     RECT  21.708 37.589 27.702 38.189 ;
     RECT  21.708 38.189 27.594 38.347 ;
     RECT  30.564 37.499 31.086 38.399 ;
     RECT  28.548 37.589 29.697 38.669 ;
     RECT  21.06 38.347 27.594 38.777 ;
     RECT  31.824 37.499 32.526 39.355 ;
     RECT  31.608 39.355 32.526 39.551 ;
     RECT  32.04 39.551 32.526 39.631 ;
     RECT  32.04 39.631 32.922 39.749 ;
     RECT  21.204 38.777 27.594 39.821 ;
     RECT  28.548 38.669 28.566 40.019 ;
     RECT  21.708 39.821 27.594 40.171 ;
     RECT  21.708 40.171 27.846 40.289 ;
     RECT  30.564 38.399 30.582 40.361 ;
     RECT  32.04 39.749 32.058 40.441 ;
     RECT  32.904 39.749 32.922 40.469 ;
     RECT  21.708 40.289 27.522 40.559 ;
     RECT  31.536 40.441 32.058 40.559 ;
     RECT  31.536 40.559 31.626 40.567 ;
     RECT  26.748 40.559 27.45 40.631 ;
     RECT  31.248 40.567 31.626 40.739 ;
     RECT  2.415 27.941 2.697 40.787 ;
     RECT  7.815 29.759 8.097 40.787 ;
     RECT  13.215 33.917 13.497 40.787 ;
     RECT  18.615 34.187 18.897 40.787 ;
     RECT  29.415 38.669 29.697 40.787 ;
     RECT  34.815 32.873 35.097 40.787 ;
     RECT  40.215 31.415 40.497 40.787 ;
     RECT  45.615 2.413 45.897 40.787 ;
     RECT  51.015 2.413 51.297 40.787 ;
     RECT  56.415 2.413 56.697 40.787 ;
     RECT  61.815 2.413 62.097 40.787 ;
     RECT  22.212 40.559 25.686 40.829 ;
     RECT  26.748 40.631 26.946 40.829 ;
     RECT  31.536 40.739 31.626 40.865 ;
     RECT  26.748 40.829 26.766 40.925 ;
     RECT  22.212 40.829 25.65 41.021 ;
     RECT  2.415 40.787 2.505 41.057 ;
     RECT  7.815 40.787 7.905 41.057 ;
     RECT  13.215 40.787 13.305 41.057 ;
     RECT  18.615 40.787 18.705 41.057 ;
     RECT  29.415 40.787 29.505 41.057 ;
     RECT  34.815 40.787 34.905 41.057 ;
     RECT  40.215 40.787 40.305 41.057 ;
     RECT  45.615 40.787 45.705 41.057 ;
     RECT  51.015 40.787 51.105 41.057 ;
     RECT  56.415 40.787 56.505 41.057 ;
     RECT  61.815 40.787 61.905 41.057 ;
     RECT  23.94 41.021 24.642 41.213 ;
     RECT  31.536 40.865 31.554 42.173 ;
     RECT  22.212 41.021 23.058 42.221 ;
     RECT  22.356 42.221 22.986 42.317 ;
     RECT  23.976 41.213 24.642 42.811 ;
     RECT  23.976 42.811 25.038 42.941 ;
     RECT  22.356 42.317 22.374 43.085 ;
     RECT  23.976 42.941 24.57 43.085 ;
    LAYER M4 ;
     RECT  2.285 25.056 2.408 25.08 ;
     RECT  2.293 26.208 2.408 26.232 ;
     RECT  2.408 2.148 2.512 41.052 ;
     RECT  2.512 2.418 2.704 40.782 ;
     RECT  2.704 27.888 3.565 27.96 ;
     RECT  2.704 23.904 3.733 23.928 ;
     RECT  3.733 23.856 3.805 23.928 ;
     RECT  2.704 25.008 3.805 25.032 ;
     RECT  2.704 26.304 3.973 26.856 ;
     RECT  3.805 23.856 4.021 25.032 ;
     RECT  4.268 16.416 4.355 16.44 ;
     RECT  4.021 23.664 4.588 25.032 ;
     RECT  3.973 26.016 5.213 26.856 ;
     RECT  5.213 26.208 5.245 26.856 ;
     RECT  3.565 27.888 5.245 27.912 ;
     RECT  5.245 26.208 5.821 27.912 ;
     RECT  4.921 23.328 6.181 23.4 ;
     RECT  4.588 24.528 6.181 25.032 ;
     RECT  5.821 26.208 6.181 28.152 ;
     RECT  6.181 23.328 6.293 25.032 ;
     RECT  6.181 26.208 6.323 29.112 ;
     RECT  6.323 26.592 6.361 29.112 ;
     RECT  6.293 23.376 6.437 25.032 ;
     RECT  6.361 26.592 6.505 29.448 ;
     RECT  6.505 26.592 6.589 30.216 ;
     RECT  6.437 23.568 7.333 25.032 ;
     RECT  7.333 23.568 7.657 25.272 ;
     RECT  7.657 23.568 7.808 25.464 ;
     RECT  6.589 26.592 7.808 29.448 ;
     RECT  6.517 33.552 7.808 33.576 ;
     RECT  7.808 2.148 7.912 41.052 ;
     RECT  7.912 2.418 8.104 40.782 ;
     RECT  8.104 28.176 8.531 29.112 ;
     RECT  8.104 26.64 9.059 26.76 ;
     RECT  8.531 28.176 9.137 28.536 ;
     RECT  8.104 23.568 9.241 25.608 ;
     RECT  9.059 26.64 9.241 26.664 ;
     RECT  9.241 23.568 9.493 26.664 ;
     RECT  9.493 23.376 9.533 26.664 ;
     RECT  9.589 21.12 9.673 21.144 ;
     RECT  9.673 21.12 9.676 21.24 ;
     RECT  9.137 28.368 9.733 28.536 ;
     RECT  9.533 23.376 9.785 23.592 ;
     RECT  9.701 30.24 9.785 30.264 ;
     RECT  9.733 28.368 9.893 29.064 ;
     RECT  9.533 24.576 9.929 26.664 ;
     RECT  9.676 21.216 9.961 21.24 ;
     RECT  9.929 24.576 10.037 26.232 ;
     RECT  9.961 21.216 10.045 21.672 ;
     RECT  9.893 29.04 10.357 29.064 ;
     RECT  9.785 23.376 10.397 23.544 ;
     RECT  10.316 27.312 10.403 27.336 ;
     RECT  10.357 29.04 10.969 29.112 ;
     RECT  10.789 23.856 11.041 23.88 ;
     RECT  10.037 25.056 11.221 26.232 ;
     RECT  11.221 25.056 11.413 26.52 ;
     RECT  11.413 25.008 11.477 26.52 ;
     RECT  10.969 28.032 11.513 29.112 ;
     RECT  11.041 23.856 11.621 23.928 ;
     RECT  10.045 21.216 11.869 21.24 ;
     RECT  11.477 25.008 11.869 26.088 ;
     RECT  11.513 28.032 12.625 28.056 ;
     RECT  11.513 29.088 12.625 29.112 ;
     RECT  12.625 28.032 12.697 29.112 ;
     RECT  12.697 28.032 12.805 29.208 ;
     RECT  10.825 31.776 12.805 31.8 ;
     RECT  11.869 24.912 12.841 26.088 ;
     RECT  11.869 20.928 12.913 21.24 ;
     RECT  12.913 20.928 12.949 21.336 ;
     RECT  12.841 24.912 13.093 26.136 ;
     RECT  12.949 20.928 13.121 21.432 ;
     RECT  13.021 22.512 13.165 22.536 ;
     RECT  11.621 23.904 13.165 23.928 ;
     RECT  13.165 22.512 13.201 23.928 ;
     RECT  13.093 24.912 13.201 26.328 ;
     RECT  13.121 20.928 13.208 21.48 ;
     RECT  13.201 22.512 13.208 26.328 ;
     RECT  12.805 28.032 13.208 29.256 ;
     RECT  12.805 31.776 13.208 32.52 ;
     RECT  8.104 33.552 13.208 33.576 ;
     RECT  13.208 2.148 13.312 41.052 ;
     RECT  13.312 2.418 13.504 40.782 ;
     RECT  13.504 24.912 13.529 26.28 ;
     RECT  13.529 25.008 13.667 26.28 ;
     RECT  13.504 32.496 13.715 32.52 ;
     RECT  13.504 28.704 13.781 31.368 ;
     RECT  13.504 20.544 13.817 21.48 ;
     RECT  13.817 20.544 13.889 21.432 ;
     RECT  13.781 29.856 14.003 31.368 ;
     RECT  13.504 22.512 14.105 23.928 ;
     RECT  13.781 28.704 14.605 28.728 ;
     RECT  13.667 25.104 14.684 26.28 ;
     RECT  13.504 27.264 14.684 27.336 ;
     RECT  14.684 25.104 14.749 27.336 ;
     RECT  14.749 25.104 14.897 27.432 ;
     RECT  13.889 20.544 15.037 21.336 ;
     RECT  15.037 20.544 15.073 21.432 ;
     RECT  14.605 28.416 15.073 28.728 ;
     RECT  14.003 29.856 15.073 30.792 ;
     RECT  14.105 22.608 15.077 23.928 ;
     RECT  15.073 20.544 15.221 21.528 ;
     RECT  14.897 25.104 15.293 26.808 ;
     RECT  13.504 33.552 15.437 33.672 ;
     RECT  15.356 15.984 15.443 16.008 ;
     RECT  15.073 28.416 15.505 30.792 ;
     RECT  15.437 33.552 15.505 33.576 ;
     RECT  15.293 25.104 15.577 25.464 ;
     RECT  15.505 28.08 15.644 30.792 ;
     RECT  14.929 32.16 15.644 32.184 ;
     RECT  15.644 28.08 15.725 32.184 ;
     RECT  15.725 28.08 15.731 31.368 ;
     RECT  15.505 33.36 15.797 33.576 ;
     RECT  15.577 25.056 15.829 25.464 ;
     RECT  15.293 26.544 15.865 26.808 ;
     RECT  15.731 28.08 15.865 30.936 ;
     RECT  15.077 22.8 16.193 23.928 ;
     RECT  15.797 33.552 16.513 33.576 ;
     RECT  16.193 22.8 16.585 23.544 ;
     RECT  15.221 21.072 16.657 21.528 ;
     RECT  16.585 22.56 16.657 23.544 ;
     RECT  15.865 26.544 16.757 30.936 ;
     RECT  16.757 26.544 16.841 31.32 ;
     RECT  16.841 26.544 16.883 31.08 ;
     RECT  16.657 21.072 16.981 23.544 ;
     RECT  15.829 24.912 17.017 25.464 ;
     RECT  16.883 26.544 17.017 27.192 ;
     RECT  17.017 24.912 17.084 27.192 ;
     RECT  16.883 28.656 17.165 30.936 ;
     RECT  16.513 33.552 17.165 34.2 ;
     RECT  17.084 24.864 17.171 27.192 ;
     RECT  17.165 33.552 17.377 33.96 ;
     RECT  17.165 29.328 17.417 30.936 ;
     RECT  15.217 19.344 17.489 19.368 ;
     RECT  17.377 33.36 17.597 33.96 ;
     RECT  16.981 20.88 17.845 23.544 ;
     RECT  17.845 20.16 18.241 23.544 ;
     RECT  17.171 24.912 18.241 27.192 ;
     RECT  17.417 29.328 18.313 30.84 ;
     RECT  18.241 20.16 18.349 27.192 ;
     RECT  17.593 4.272 18.608 4.296 ;
     RECT  15.397 10.128 18.608 10.152 ;
     RECT  15.505 16.032 18.608 16.056 ;
     RECT  18.349 20.16 18.608 27.912 ;
     RECT  18.313 29.28 18.608 30.84 ;
     RECT  17.953 32.496 18.608 32.52 ;
     RECT  17.597 33.648 18.608 33.96 ;
     RECT  18.608 2.148 18.712 41.052 ;
     RECT  18.712 2.418 18.904 40.782 ;
     RECT  18.904 26.112 19.001 27.336 ;
     RECT  18.904 22.176 19.109 23.064 ;
     RECT  18.904 24.096 19.361 25.032 ;
     RECT  19.361 24.096 19.541 24.504 ;
     RECT  18.904 30.24 19.541 34.152 ;
     RECT  19.541 31.344 19.613 34.152 ;
     RECT  19.109 22.176 19.649 22.824 ;
     RECT  19.609 1.104 19.753 1.128 ;
     RECT  18.904 9.36 19.793 10.152 ;
     RECT  19.753 1.104 19.825 1.752 ;
     RECT  19.825 0.144 19.859 1.752 ;
     RECT  19.793 9.36 19.859 9.768 ;
     RECT  18.904 20.544 19.865 20.76 ;
     RECT  19.859 0.144 19.889 1.224 ;
     RECT  18.904 6.672 19.973 7.8 ;
     RECT  19.897 9.12 19.981 9.144 ;
     RECT  19.541 30.24 20.06 30.264 ;
     RECT  20.06 29.376 20.147 30.264 ;
     RECT  19.613 31.632 20.401 34.152 ;
     RECT  19.001 26.208 20.473 27.336 ;
     RECT  20.401 31.632 20.653 34.344 ;
     RECT  19.649 22.176 20.725 22.488 ;
     RECT  20.473 25.776 20.729 27.336 ;
     RECT  20.147 30.24 20.797 30.264 ;
     RECT  20.653 31.344 20.797 34.344 ;
     RECT  19.889 0.096 20.861 1.224 ;
     RECT  19.865 20.736 20.905 20.76 ;
     RECT  20.725 22.176 20.909 22.536 ;
     RECT  19.541 24.48 20.977 24.504 ;
     RECT  20.861 0.096 21.011 1.752 ;
     RECT  20.797 30.24 21.125 34.344 ;
     RECT  21.049 38.352 21.155 38.376 ;
     RECT  21.125 34.32 21.169 34.344 ;
     RECT  20.977 24.48 21.265 24.552 ;
     RECT  20.905 20.16 21.269 20.76 ;
     RECT  21.26 39.12 21.301 39.144 ;
     RECT  21.011 0.096 21.305 0.6 ;
     RECT  21.301 39.12 21.347 39.912 ;
     RECT  21.085 2.832 21.377 2.856 ;
     RECT  21.125 30.24 21.404 33.048 ;
     RECT  20.909 22.512 21.409 22.536 ;
     RECT  21.265 23.952 21.409 24.552 ;
     RECT  21.404 29.616 21.491 33.048 ;
     RECT  21.011 1.728 21.541 1.752 ;
     RECT  21.269 20.16 21.557 20.184 ;
     RECT  20.293 19.152 21.589 19.176 ;
     RECT  21.589 18.816 21.629 19.176 ;
     RECT  21.491 30.24 21.629 33.048 ;
     RECT  19.973 7.344 21.737 7.8 ;
     RECT  21.305 0.096 21.779 0.552 ;
     RECT  21.409 22.512 21.829 24.552 ;
     RECT  20.729 25.776 21.829 27.24 ;
     RECT  21.829 22.512 21.916 27.24 ;
     RECT  21.916 22.512 21.989 24.504 ;
     RECT  21.661 3.84 22.165 3.864 ;
     RECT  21.949 28.416 22.165 28.44 ;
     RECT  21.541 1.728 22.169 2.28 ;
     RECT  22.169 1.728 22.205 1.848 ;
     RECT  22.165 28.272 22.213 28.44 ;
     RECT  21.629 30.24 22.277 31.368 ;
     RECT  22.165 3.552 22.313 3.864 ;
     RECT  22.201 42.192 22.345 42.216 ;
     RECT  20.437 6 22.417 6.024 ;
     RECT  21.347 39.744 22.417 39.912 ;
     RECT  21.989 23.328 22.421 24.504 ;
     RECT  21.779 0.096 22.525 0.216 ;
     RECT  21.629 32.352 22.529 33.048 ;
     RECT  22.345 42.192 22.547 43.08 ;
     RECT  22.213 28.272 22.565 29.112 ;
     RECT  21.737 7.392 22.637 7.8 ;
     RECT  22.205 1.728 22.673 1.8 ;
     RECT  22.417 39.744 22.739 40.488 ;
     RECT  22.313 3.84 22.741 3.864 ;
     RECT  21.629 18.816 22.741 18.84 ;
     RECT  22.7 20.304 22.741 20.328 ;
     RECT  22.277 30.816 22.741 31.368 ;
     RECT  22.529 32.352 22.741 32.52 ;
     RECT  22.741 18.816 22.787 20.328 ;
     RECT  22.525 0.048 22.789 0.216 ;
     RECT  22.547 42.192 22.789 42.984 ;
     RECT  22.789 38.448 22.813 38.472 ;
     RECT  21.916 26.208 22.817 27.24 ;
     RECT  22.789 0.048 22.876 0.6 ;
     RECT  22.813 38.448 22.876 38.76 ;
     RECT  22.597 34.176 22.885 34.2 ;
     RECT  22.417 5.712 22.957 6.024 ;
     RECT  22.876 38.736 22.957 38.76 ;
     RECT  22.739 39.744 22.957 39.768 ;
     RECT  22.421 23.328 22.961 23.352 ;
     RECT  22.637 7.392 22.997 7.416 ;
     RECT  22.565 28.272 22.997 28.68 ;
     RECT  22.957 38.736 22.997 39.768 ;
     RECT  22.789 42.048 23.075 42.984 ;
     RECT  22.787 19.776 23.245 20.328 ;
     RECT  23.173 21.936 23.389 21.96 ;
     RECT  22.876 0.048 23.393 0.216 ;
     RECT  23.075 42.288 23.411 42.984 ;
     RECT  22.673 1.728 23.465 1.752 ;
     RECT  22.921 36.528 23.569 36.552 ;
     RECT  22.741 3.84 23.612 4.536 ;
     RECT  22.957 5.52 23.612 6.024 ;
     RECT  23.393 0.048 23.717 0.12 ;
     RECT  22.817 26.208 23.749 26.856 ;
     RECT  23.605 43.008 23.89 43.032 ;
     RECT  23.749 26.112 23.893 26.856 ;
     RECT  22.997 28.272 23.893 28.296 ;
     RECT  23.245 19.776 23.929 20.424 ;
     RECT  23.389 21.936 23.929 22.728 ;
     RECT  22.921 40.848 23.929 41.016 ;
     RECT  23.893 26.112 24.001 28.296 ;
     RECT  23.929 29.328 24.001 29.352 ;
     RECT  23.612 3.84 24.008 6.024 ;
     RECT  18.904 16.032 24.008 16.056 ;
     RECT  23.929 19.776 24.008 22.728 ;
     RECT  22.421 24.48 24.008 24.504 ;
     RECT  24.001 26.112 24.008 29.352 ;
     RECT  22.741 30.816 24.008 32.52 ;
     RECT  22.885 33.6 24.008 34.2 ;
     RECT  23.569 36.528 24.008 37.032 ;
     RECT  22.997 38.736 24.008 39.528 ;
     RECT  23.929 40.848 24.008 41.208 ;
     RECT  24.008 2.148 24.112 41.208 ;
     RECT  24.112 2.418 24.304 41.208 ;
     RECT  23.717 0.048 24.365 0.072 ;
     RECT  24.304 5.808 24.401 5.832 ;
     RECT  24.304 38.736 24.401 39.528 ;
     RECT  24.304 30.816 24.419 35.304 ;
     RECT  24.304 36.528 24.419 37.608 ;
     RECT  24.304 40.896 24.437 41.208 ;
     RECT  24.419 30.816 24.467 34.584 ;
     RECT  24.304 19.104 24.473 21 ;
     RECT  24.304 22.56 24.508 29.688 ;
     RECT  24.467 30.864 24.509 34.584 ;
     RECT  23.89 43.008 24.517 43.08 ;
     RECT  24.304 3.84 24.545 4.536 ;
     RECT  24.509 30.912 24.581 33.96 ;
     RECT  24.517 42.192 24.581 43.08 ;
     RECT  24.581 42.192 24.653 42.936 ;
     RECT  24.581 31.296 24.797 33.96 ;
     RECT  24.797 32.448 24.941 33.96 ;
     RECT  24.304 15.696 24.995 16.2 ;
     RECT  24.473 19.104 24.995 20.568 ;
     RECT  24.401 39.216 25.013 39.528 ;
     RECT  24.653 42.768 25.043 42.936 ;
     RECT  25.043 42.816 25.049 42.936 ;
     RECT  25.049 42.912 25.084 42.936 ;
     RECT  24.508 26.112 25.121 29.688 ;
     RECT  25.121 26.64 25.157 29.688 ;
     RECT  24.437 40.896 25.336 41.016 ;
     RECT  25.013 39.216 25.405 39.24 ;
     RECT  25.336 40.848 25.469 41.016 ;
     RECT  25.405 38.736 25.489 39.24 ;
     RECT  25.469 40.752 25.553 41.016 ;
     RECT  25.477 1.728 25.619 1.752 ;
     RECT  24.508 22.56 25.621 24.504 ;
     RECT  25.553 40.896 25.661 41.016 ;
     RECT  24.941 32.448 25.697 32.76 ;
     RECT  25.621 22.56 25.705 24.6 ;
     RECT  25.157 26.64 25.733 28.776 ;
     RECT  25.733 28.464 25.805 28.776 ;
     RECT  24.419 36.624 25.805 37.608 ;
     RECT  24.995 19.248 25.837 20.568 ;
     RECT  25.837 19.248 25.909 21.528 ;
     RECT  25.705 22.56 25.909 24.12 ;
     RECT  25.909 19.248 26.125 24.12 ;
     RECT  24.797 31.296 26.125 31.32 ;
     RECT  25.489 39.216 26.165 39.24 ;
     RECT  25.697 32.736 26.453 32.76 ;
     RECT  26.125 18.96 26.633 24.12 ;
     RECT  26.633 18.96 26.741 21.672 ;
     RECT  24.995 15.696 26.773 16.056 ;
     RECT  25.805 36.72 26.773 37.608 ;
     RECT  25.661 40.896 26.777 40.92 ;
     RECT  26.741 20.112 26.885 21.672 ;
     RECT  24.545 3.84 26.993 3.864 ;
     RECT  25.733 26.64 27.025 27.432 ;
     RECT  26.633 23.232 27.209 24.12 ;
     RECT  26.773 36.72 27.251 38.184 ;
     RECT  26.125 30.48 27.349 31.32 ;
     RECT  27.349 30.144 27.353 31.32 ;
     RECT  25.805 28.464 27.385 28.488 ;
     RECT  26.521 39.84 27.389 39.864 ;
     RECT  26.089 34.464 27.497 34.488 ;
     RECT  27.353 30.144 27.533 31.176 ;
     RECT  27.251 37.824 27.731 38.184 ;
     RECT  27.533 30.144 27.745 30.168 ;
     RECT  26.741 18.96 27.929 18.984 ;
     RECT  26.885 20.304 27.965 21.672 ;
     RECT  27.745 29.472 27.965 30.168 ;
     RECT  27.209 23.232 28.141 23.64 ;
     RECT  27.025 25.68 28.213 27.432 ;
     RECT  27.385 28.416 28.213 28.488 ;
     RECT  27.965 30.144 28.253 30.168 ;
     RECT  28.213 25.68 28.259 28.488 ;
     RECT  27.251 36.72 28.259 36.744 ;
     RECT  28.141 22.848 28.465 23.64 ;
     RECT  28.172 32.928 28.465 32.952 ;
     RECT  28.259 25.68 28.753 28.44 ;
     RECT  27.965 21.648 28.825 21.672 ;
     RECT  28.465 22.8 28.825 23.64 ;
     RECT  28.969 30.192 28.981 30.216 ;
     RECT  28.681 31.2 28.981 31.224 ;
     RECT  28.981 30.192 29.041 31.224 ;
     RECT  28.465 32.928 29.041 33.048 ;
     RECT  28.825 21.648 29.077 23.64 ;
     RECT  28.753 24.912 29.077 28.44 ;
     RECT  27.965 20.304 29.269 20.616 ;
     RECT  29.041 30.192 29.365 33.048 ;
     RECT  26.773 15.552 29.408 16.056 ;
     RECT  29.269 19.344 29.408 20.616 ;
     RECT  29.077 21.648 29.408 28.44 ;
     RECT  29.365 29.616 29.408 33.048 ;
     RECT  29.077 34.08 29.408 34.104 ;
     RECT  27.731 38.16 29.408 38.184 ;
     RECT  29.408 2.148 29.512 41.052 ;
     RECT  29.512 2.418 29.704 40.782 ;
     RECT  29.704 20.064 30.017 27.72 ;
     RECT  30.017 20.064 30.089 24.552 ;
     RECT  30.017 25.632 30.233 27.72 ;
     RECT  29.704 32.016 30.377 32.04 ;
     RECT  29.704 28.8 30.412 30.936 ;
     RECT  29.704 38.16 30.757 38.184 ;
     RECT  30.412 30.672 30.773 30.936 ;
     RECT  30.089 20.064 30.805 21.192 ;
     RECT  30.773 30.768 30.805 30.936 ;
     RECT  30.757 38.16 30.805 38.808 ;
     RECT  30.805 30.768 30.845 31.368 ;
     RECT  30.769 33.456 30.853 33.48 ;
     RECT  30.805 38.064 30.853 38.808 ;
     RECT  30.853 38.064 30.899 39.384 ;
     RECT  30.899 38.064 30.947 38.184 ;
     RECT  30.805 19.632 31.237 21.192 ;
     RECT  30.089 22.272 31.237 24.552 ;
     RECT  31.237 19.632 31.277 24.552 ;
     RECT  30.233 25.632 31.333 26.664 ;
     RECT  30.233 27.696 31.333 27.72 ;
     RECT  31.333 25.632 31.379 27.72 ;
     RECT  31.277 20.592 31.421 24.552 ;
     RECT  31.379 25.632 31.421 26.76 ;
     RECT  30.845 31.344 31.421 31.368 ;
     RECT  31.417 0.576 31.571 0.6 ;
     RECT  31.484 4.512 31.571 4.536 ;
     RECT  29.704 15.552 31.571 16.056 ;
     RECT  31.525 42.144 31.609 42.168 ;
     RECT  31.421 22.752 31.619 24.552 ;
     RECT  30.412 28.8 31.619 29.112 ;
     RECT  30.899 39.36 31.637 39.384 ;
     RECT  31.573 27.744 31.66 27.768 ;
     RECT  31.421 20.592 31.673 21.672 ;
     RECT  31.673 20.592 31.709 21.192 ;
     RECT  31.709 20.736 31.715 21.192 ;
     RECT  31.619 23.328 31.715 24.552 ;
     RECT  31.421 26.112 31.781 26.76 ;
     RECT  31.715 23.328 32.105 23.688 ;
     RECT  32.105 23.328 32.285 23.352 ;
     RECT  32.137 30.912 32.581 30.936 ;
     RECT  31.715 21.168 32.645 21.192 ;
     RECT  32.581 30.528 32.668 30.936 ;
     RECT  31.781 26.304 32.857 26.76 ;
     RECT  31.619 28.944 32.857 29.112 ;
     RECT  32.668 30.912 32.897 30.936 ;
     RECT  30.805 32.448 32.965 32.472 ;
     RECT  32.965 32.208 33.005 32.472 ;
     RECT  32.857 28.512 33.013 29.112 ;
     RECT  33.005 32.208 33.109 32.232 ;
     RECT  33.013 28.512 33.185 29.208 ;
     RECT  32.857 25.584 33.685 26.76 ;
     RECT  33.685 25.584 34.189 27.24 ;
     RECT  33.185 28.512 34.189 29.064 ;
     RECT  33.109 31.776 34.213 32.232 ;
     RECT  34.213 31.536 34.225 32.232 ;
     RECT  34.225 31.392 34.549 32.232 ;
     RECT  31.571 16.032 34.808 16.056 ;
     RECT  33.973 23.136 34.808 23.16 ;
     RECT  34.189 25.584 34.808 29.064 ;
     RECT  34.549 31.392 34.808 32.76 ;
     RECT  34.808 2.148 34.912 41.052 ;
     RECT  34.912 2.418 35.104 40.782 ;
     RECT  35.104 28.944 35.309 31.416 ;
     RECT  35.309 29.088 35.381 31.416 ;
     RECT  35.104 25.872 36.241 27.912 ;
     RECT  35.381 29.088 36.275 31.368 ;
     RECT  36.275 30.432 36.281 31.368 ;
     RECT  35.104 24.384 36.601 24.744 ;
     RECT  36.241 25.776 36.601 27.912 ;
     RECT  36.281 30.432 36.677 31.32 ;
     RECT  36.601 24.384 37.177 27.912 ;
     RECT  36.275 29.088 37.177 29.112 ;
     RECT  37.177 24.384 37.505 29.112 ;
     RECT  37.505 26.736 37.609 29.112 ;
     RECT  35.104 16.032 37.619 16.056 ;
     RECT  37.505 24.384 37.649 25.128 ;
     RECT  37.609 26.736 37.669 29.4 ;
     RECT  37.669 26.736 37.756 30.024 ;
     RECT  37.756 26.736 38.092 29.928 ;
     RECT  38.092 28.512 38.225 29.928 ;
     RECT  38.225 28.512 38.549 28.536 ;
     RECT  38.092 26.736 38.761 27.336 ;
     RECT  38.225 29.904 38.801 29.928 ;
     RECT  37.649 24.384 39.053 24.936 ;
     RECT  39.053 24.672 39.085 24.936 ;
     RECT  38.761 26.64 39.085 27.336 ;
     RECT  36.677 31.296 39.197 31.32 ;
     RECT  39.085 24.672 39.203 27.336 ;
     RECT  39.836 28.416 39.877 28.44 ;
     RECT  39.203 24.672 40.208 24.696 ;
     RECT  39.203 25.776 40.208 27.336 ;
     RECT  39.877 28.416 40.208 29.064 ;
     RECT  40.208 2.148 40.312 41.052 ;
     RECT  40.312 2.418 40.504 40.782 ;
     RECT  40.504 29.04 41.069 29.064 ;
     RECT  40.504 26.64 43.571 26.664 ;
     RECT  45.608 2.148 45.712 41.052 ;
     RECT  45.712 2.418 45.904 40.782 ;
     RECT  51.008 2.148 51.112 41.052 ;
     RECT  51.112 2.418 51.304 40.782 ;
     RECT  56.408 2.148 56.512 41.052 ;
     RECT  56.512 2.418 56.704 40.782 ;
     RECT  61.808 2.148 61.912 41.052 ;
     RECT  61.912 2.418 62.104 40.782 ;
    LAYER M5 ;
     RECT  19.824 0.016 22.824 0.611 ;
     RECT  19.824 0.611 22.632 1.235 ;
     RECT  19.824 1.235 19.848 1.763 ;
     RECT  20.88 1.235 22.632 1.763 ;
     RECT  21.552 1.763 22.632 1.811 ;
     RECT  2.4 2.137 2.52 2.151 ;
     RECT  7.8 2.137 7.92 2.151 ;
     RECT  13.2 2.137 13.32 2.151 ;
     RECT  18.6 2.137 18.72 2.151 ;
     RECT  24 2.137 24.12 2.151 ;
     RECT  29.4 2.137 29.52 2.151 ;
     RECT  34.8 2.137 34.92 2.151 ;
     RECT  40.2 2.137 40.32 2.151 ;
     RECT  45.6 2.137 45.72 2.151 ;
     RECT  51 2.137 51.12 2.151 ;
     RECT  56.4 2.137 56.52 2.151 ;
     RECT  61.8 2.137 61.92 2.151 ;
     RECT  21.552 1.811 22.152 2.195 ;
     RECT  22.128 2.195 22.152 2.291 ;
     RECT  24 2.151 24.312 3.829 ;
     RECT  23.664 3.829 24.312 4.501 ;
     RECT  22.8 4.501 24.312 5.171 ;
     RECT  22.8 5.171 22.824 6.035 ;
     RECT  18.6 2.151 18.912 6.661 ;
     RECT  18.6 6.661 19.896 7.765 ;
     RECT  18.6 7.765 19.944 9.155 ;
     RECT  18.6 9.155 19.848 9.779 ;
     RECT  18.6 9.779 19.224 10.163 ;
     RECT  31.536 4.501 31.56 15.587 ;
     RECT  24 5.171 24.312 16.165 ;
     RECT  25.92 15.877 25.944 16.165 ;
     RECT  24 16.165 25.944 19.139 ;
     RECT  29.4 2.151 29.712 19.333 ;
     RECT  24 19.139 24.888 19.811 ;
     RECT  25.92 19.139 25.944 19.909 ;
     RECT  29.28 19.333 29.712 20.099 ;
     RECT  22.752 18.805 22.776 20.339 ;
     RECT  30.816 19.621 30.84 20.725 ;
     RECT  30.816 20.725 31.704 21.203 ;
     RECT  15.408 10.117 15.432 21.347 ;
     RECT  25.92 19.909 26.232 21.397 ;
     RECT  9.6 21.109 9.624 21.637 ;
     RECT  25.92 21.397 26.376 21.683 ;
     RECT  26.352 21.683 26.376 22.115 ;
     RECT  13.2 2.151 13.512 22.597 ;
     RECT  31.68 21.203 31.704 22.741 ;
     RECT  29.4 20.099 29.712 23.317 ;
     RECT  31.584 22.741 31.704 23.363 ;
     RECT  16.848 21.637 16.872 23.509 ;
     RECT  9.6 21.637 10.008 23.555 ;
     RECT  4.32 16.405 4.344 23.653 ;
     RECT  4.032 23.653 4.344 23.845 ;
     RECT  7.8 2.151 8.112 23.845 ;
     RECT  3.744 23.845 4.344 23.893 ;
     RECT  6.288 23.557 6.312 24.085 ;
     RECT  7.68 23.845 8.112 24.085 ;
     RECT  29.4 23.317 30.36 24.515 ;
     RECT  31.68 23.363 31.704 24.517 ;
     RECT  31.344 24.517 31.704 24.563 ;
     RECT  25.632 23.317 25.656 24.611 ;
     RECT  6.288 24.085 8.112 24.659 ;
     RECT  9.6 23.555 9.624 24.659 ;
     RECT  2.4 2.151 2.712 25.045 ;
     RECT  16.848 23.509 17.16 25.093 ;
     RECT  18.6 10.163 18.912 25.093 ;
     RECT  13.2 22.597 14.232 25.139 ;
     RECT  24 19.811 24.312 25.381 ;
     RECT  10.272 25.045 10.296 25.715 ;
     RECT  16.848 25.093 18.912 25.715 ;
     RECT  13.2 25.139 13.656 25.813 ;
     RECT  11.424 24.997 11.448 26.005 ;
     RECT  10.848 26.005 11.448 26.051 ;
     RECT  31.344 24.563 31.368 26.101 ;
     RECT  2.304 25.045 2.712 26.243 ;
     RECT  10.848 26.051 10.872 26.243 ;
     RECT  13.104 25.813 13.656 26.243 ;
     RECT  21.84 24.517 21.864 26.243 ;
     RECT  33.648 25.573 33.672 26.243 ;
     RECT  39.168 25.573 39.192 26.243 ;
     RECT  13.104 26.243 13.608 26.339 ;
     RECT  6.288 24.659 6.312 26.581 ;
     RECT  6.192 26.581 6.312 26.627 ;
     RECT  34.8 2.151 35.112 26.629 ;
     RECT  2.4 26.243 2.712 26.725 ;
     RECT  3.744 23.893 4.536 26.725 ;
     RECT  7.488 24.659 8.112 26.725 ;
     RECT  34.8 26.629 35.208 26.771 ;
     RECT  7.488 26.725 9.048 26.819 ;
     RECT  24 25.381 24.456 26.821 ;
     RECT  2.4 26.725 4.536 26.867 ;
     RECT  24 26.821 24.504 27.061 ;
     RECT  34.8 26.771 35.112 27.205 ;
     RECT  24 27.061 24.552 27.731 ;
     RECT  31.344 26.101 31.608 27.731 ;
     RECT  37.584 16.021 37.608 27.733 ;
     RECT  6.192 26.627 6.216 27.877 ;
     RECT  7.68 26.819 9.048 27.877 ;
     RECT  18.6 25.715 18.912 27.877 ;
     RECT  4.512 26.867 4.536 27.923 ;
     RECT  2.4 26.867 3.528 27.971 ;
     RECT  6.192 27.877 9.048 28.403 ;
     RECT  40.2 2.151 40.512 28.405 ;
     RECT  14.736 26.245 14.76 28.451 ;
     RECT  10.368 27.301 10.392 28.501 ;
     RECT  34.224 27.205 35.112 28.547 ;
     RECT  37.584 27.733 38.04 28.547 ;
     RECT  31.584 27.731 31.608 28.835 ;
     RECT  16.848 25.715 16.872 28.981 ;
     RECT  39.888 28.405 40.512 29.075 ;
     RECT  33.024 28.501 33.048 29.077 ;
     RECT  6.192 28.403 8.52 29.123 ;
     RECT  9.744 28.501 10.392 29.123 ;
     RECT  21.456 27.205 22.248 29.123 ;
     RECT  32.592 29.077 33.048 29.219 ;
     RECT  13.2 26.339 13.608 29.267 ;
     RECT  6.816 29.123 8.112 29.459 ;
     RECT  36.288 26.533 36.312 29.653 ;
     RECT  29.4 24.515 29.712 29.941 ;
     RECT  28.224 27.685 28.248 30.181 ;
     RECT  29.4 29.941 30.36 30.181 ;
     RECT  9.744 29.123 9.768 30.275 ;
     RECT  20.112 29.365 20.136 30.275 ;
     RECT  21.456 29.123 21.48 30.275 ;
     RECT  32.592 29.219 32.616 30.563 ;
     RECT  28.224 30.181 30.36 30.661 ;
     RECT  13.2 29.267 13.512 30.757 ;
     RECT  16.512 28.981 16.872 30.757 ;
     RECT  15.696 30.757 16.872 30.803 ;
     RECT  28.224 30.661 30.744 30.803 ;
     RECT  18.384 27.877 18.912 30.851 ;
     RECT  36.24 29.653 36.312 30.851 ;
     RECT  28.224 30.803 30.36 30.947 ;
     RECT  36.24 30.851 36.264 30.947 ;
     RECT  16.8 30.803 16.872 31.091 ;
     RECT  37.584 28.547 37.704 31.331 ;
     RECT  13.2 30.757 13.992 31.379 ;
     RECT  15.696 30.803 15.72 31.379 ;
     RECT  34.8 28.547 35.112 31.525 ;
     RECT  34.224 31.525 35.112 32.243 ;
     RECT  28.224 30.947 28.248 32.437 ;
     RECT  29.4 30.947 29.712 32.437 ;
     RECT  13.2 31.379 13.512 32.485 ;
     RECT  34.56 32.243 35.112 32.771 ;
     RECT  21.12 32.197 21.144 33.059 ;
     RECT  6.528 30.181 6.552 33.587 ;
     RECT  13.2 32.485 13.704 33.683 ;
     RECT  16.8 31.091 16.824 33.683 ;
     RECT  28.224 32.437 29.712 34.115 ;
     RECT  28.224 34.115 28.248 36.709 ;
     RECT  27.696 36.709 28.248 36.755 ;
     RECT  24 27.731 24.504 36.997 ;
     RECT  23.616 36.997 24.504 37.189 ;
     RECT  27.696 36.755 27.72 37.525 ;
     RECT  23.616 37.189 24.936 37.573 ;
     RECT  27.216 37.525 27.72 37.573 ;
     RECT  26.784 37.573 27.72 37.859 ;
     RECT  30.816 32.437 30.84 38.053 ;
     RECT  30.816 38.053 30.936 38.149 ;
     RECT  26.784 37.859 27.24 38.195 ;
     RECT  30.768 38.149 30.936 38.195 ;
     RECT  21.12 34.309 21.144 38.387 ;
     RECT  23.616 37.573 25.032 38.437 ;
     RECT  22.8 38.437 25.032 38.725 ;
     RECT  30.768 38.195 30.888 38.819 ;
     RECT  30.864 38.819 30.888 39.395 ;
     RECT  21.312 39.109 21.336 39.923 ;
     RECT  22.8 38.725 25.464 40.453 ;
     RECT  22.704 40.453 25.464 40.741 ;
     RECT  22.704 40.741 25.512 40.885 ;
     RECT  2.4 27.971 2.712 41.049 ;
     RECT  7.8 29.459 8.112 41.049 ;
     RECT  13.2 33.683 13.512 41.049 ;
     RECT  18.6 30.851 18.912 41.049 ;
     RECT  29.4 34.115 29.712 41.049 ;
     RECT  34.8 32.771 35.112 41.049 ;
     RECT  40.2 29.075 40.512 41.049 ;
     RECT  45.6 2.151 45.912 41.049 ;
     RECT  51 2.151 51.312 41.049 ;
     RECT  56.4 2.151 56.712 41.049 ;
     RECT  61.8 2.151 62.112 41.049 ;
     RECT  2.4 41.049 2.52 41.063 ;
     RECT  7.8 41.049 7.92 41.063 ;
     RECT  13.2 41.049 13.32 41.063 ;
     RECT  18.6 41.049 18.72 41.063 ;
     RECT  29.4 41.049 29.52 41.063 ;
     RECT  34.8 41.049 34.92 41.063 ;
     RECT  40.2 41.049 40.32 41.063 ;
     RECT  45.6 41.049 45.72 41.063 ;
     RECT  51 41.049 51.12 41.063 ;
     RECT  56.4 41.049 56.52 41.063 ;
     RECT  61.8 41.049 61.92 41.063 ;
     RECT  22.704 40.885 25.608 42.181 ;
     RECT  22.608 42.181 25.608 43.045 ;
     RECT  22.512 43.045 25.608 43.152 ;
     RECT  19.848 1.235 20.88 1.763 ;
     RECT  22.824 5.171 24 6.035 ;
     RECT  22.776 18.805 24 20.339 ;
     RECT  24.888 19.139 25.92 19.811 ;
     RECT  29.712 19.621 30.816 21.203 ;
     RECT  8.112 21.109 9.6 24.659 ;
     RECT  24.312 23.317 25.632 24.611 ;
     RECT  30.36 23.317 31.584 23.363 ;
     RECT  30.36 23.363 31.68 24.515 ;
     RECT  17.16 23.509 18.6 25.093 ;
     RECT  6.312 23.557 7.8 23.845 ;
     RECT  2.712 23.653 4.032 23.845 ;
     RECT  2.712 23.845 3.744 26.725 ;
     RECT  6.312 23.845 7.68 24.085 ;
     RECT  31.344 24.515 31.68 24.517 ;
     RECT  24.312 24.611 24.456 25.381 ;
     RECT  6.312 24.659 7.488 26.627 ;
     RECT  10.296 25.045 11.424 25.715 ;
     RECT  13.656 25.139 14.232 26.243 ;
     RECT  33.672 25.573 34.8 26.243 ;
     RECT  39.192 25.573 40.2 26.243 ;
     RECT  10.848 25.715 11.424 26.005 ;
     RECT  13.608 26.243 14.232 26.245 ;
     RECT  21.84 26.243 21.864 27.205 ;
     RECT  34.224 26.243 34.8 27.205 ;
     RECT  13.608 26.245 14.736 28.451 ;
     RECT  35.112 26.533 36.288 26.629 ;
     RECT  36.312 26.533 37.584 30.851 ;
     RECT  6.216 26.627 7.488 26.819 ;
     RECT  35.208 26.629 36.288 26.771 ;
     RECT  35.112 26.771 36.288 29.653 ;
     RECT  6.216 26.819 7.68 27.877 ;
     RECT  3.528 26.867 4.512 27.923 ;
     RECT  9.048 27.301 10.368 28.403 ;
     RECT  28.248 27.685 29.4 30.181 ;
     RECT  16.872 27.877 18.384 30.851 ;
     RECT  8.52 28.403 10.368 28.501 ;
     RECT  8.52 28.501 9.744 29.123 ;
     RECT  31.608 28.501 33.024 28.835 ;
     RECT  33.048 28.501 34.224 28.547 ;
     RECT  32.592 28.835 33.024 29.077 ;
     RECT  6.528 29.123 6.816 29.459 ;
     RECT  13.512 29.267 13.608 30.757 ;
     RECT  18.912 29.365 20.112 30.275 ;
     RECT  20.136 29.365 21.456 30.275 ;
     RECT  6.528 29.459 7.8 30.181 ;
     RECT  35.112 29.653 36.24 30.947 ;
     RECT  6.552 30.181 7.8 33.587 ;
     RECT  15.72 30.803 16.8 31.379 ;
     RECT  36.264 30.851 37.584 30.947 ;
     RECT  28.248 30.947 29.4 32.437 ;
     RECT  29.712 30.947 30.36 32.437 ;
     RECT  13.512 31.379 13.704 32.485 ;
     RECT  29.712 32.437 30.816 38.149 ;
     RECT  21.12 33.059 21.144 34.309 ;
     RECT  28.248 34.115 29.4 36.755 ;
     RECT  29.712 38.149 30.768 38.819 ;
     RECT  29.712 38.819 30.864 39.395 ;
     RECT  21.336 39.109 22.8 39.923 ;
     RECT  22.704 39.923 22.8 40.453 ;
  END
END qkd_ctrl_kc
END LIBRARY
